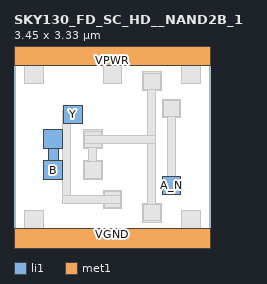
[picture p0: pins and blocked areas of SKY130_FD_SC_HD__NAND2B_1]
MACRO SKY130_FD_SC_HD__NAND2B_1
 CLASS CORE ;
 FOREIGN SKY130_FD_SC_HD__NAND2B_1 0 0 ;
 SIZE 3.45 BY 3.33 ;
 ORIGIN 0 0 ;
 SYMMETRY X Y R90 ;
 SITE unit ;
  PIN VPWR
   DIRECTION INOUT ;
   USE POWER ;
   SHAPE ABUTMENT ;
    PORT
     CLASS CORE ;
       LAYER li1 ;
        RECT 0.00000000 3.09000000 3.45000000 3.57000000 ;
       LAYER met1 ;
        RECT 0.00000000 3.09000000 3.45000000 3.57000000 ;
    END
  END VPWR

  PIN VGND
   DIRECTION INOUT ;
   USE POWER ;
   SHAPE ABUTMENT ;
    PORT
     CLASS CORE ;
       LAYER li1 ;
        RECT 0.00000000 -0.24000000 3.45000000 0.24000000 ;
       LAYER met1 ;
        RECT 0.00000000 -0.24000000 3.45000000 0.24000000 ;
    END
  END VGND

  PIN Y
   DIRECTION INOUT ;
   USE SIGNAL ;
   SHAPE ABUTMENT ;
    PORT
     CLASS CORE ;
       LAYER li1 ;
        RECT 0.87000000 2.07000000 1.20000000 2.40000000 ;
    END
  END Y

  PIN A_N
   DIRECTION INOUT ;
   USE SIGNAL ;
   SHAPE ABUTMENT ;
    PORT
     CLASS CORE ;
       LAYER li1 ;
        RECT 2.59500000 0.82500000 2.92500000 1.15500000 ;
    END
  END A_N

  PIN B
   DIRECTION INOUT ;
   USE SIGNAL ;
   SHAPE ABUTMENT ;
    PORT
     CLASS CORE ;
       LAYER li1 ;
        RECT 0.52500000 1.09500000 0.85500000 1.42500000 ;
        RECT 0.60500000 1.42500000 0.77500000 1.63500000 ;
        RECT 0.52500000 1.63500000 0.85500000 1.96500000 ;
    END
  END B

 OBS
    LAYER polycont ;
     RECT 2.67500000 0.90500000 2.84500000 1.07500000 ;
     RECT 0.60500000 1.17500000 0.77500000 1.34500000 ;
     RECT 1.29500000 1.17500000 1.46500000 1.34500000 ;
     RECT 0.60500000 1.71500000 0.77500000 1.88500000 ;
     RECT 1.29500000 1.71500000 1.46500000 1.88500000 ;
     RECT 2.67500000 2.25500000 2.84500000 2.42500000 ;

    LAYER pdiffc ;
     RECT 0.95000000 2.15000000 1.12000000 2.32000000 ;
     RECT 2.33000000 2.73000000 2.50000000 2.90000000 ;
     RECT 0.26000000 2.86000000 0.43000000 3.03000000 ;
     RECT 1.64000000 2.86000000 1.81000000 3.03000000 ;
     RECT 3.02000000 2.86000000 3.19000000 3.03000000 ;

    LAYER ndiffc ;
     RECT 0.26000000 0.30000000 0.43000000 0.47000000 ;
     RECT 3.02000000 0.30000000 3.19000000 0.47000000 ;
     RECT 2.33000000 0.43000000 2.50000000 0.60000000 ;
     RECT 1.64000000 0.66000000 1.81000000 0.83000000 ;

    LAYER li1 ;
     RECT 0.00000000 -0.24000000 3.45000000 0.24000000 ;
     RECT 0.18000000 0.24000000 0.51000000 0.55000000 ;
     RECT 2.94000000 0.24000000 3.27000000 0.55000000 ;
     RECT 2.25000000 0.35000000 2.58000000 0.68000000 ;
     RECT 1.56000000 0.58000000 1.89000000 0.91000000 ;
     RECT 2.59500000 0.82500000 2.92500000 1.15500000 ;
     RECT 1.21500000 1.09500000 1.54500000 1.42500000 ;
     RECT 0.52500000 1.09500000 0.85500000 1.42500000 ;
     RECT 0.60500000 1.42500000 0.77500000 1.63500000 ;
     RECT 0.52500000 1.63500000 0.85500000 1.96500000 ;
     RECT 1.21500000 1.63500000 1.54500000 1.96500000 ;
     RECT 0.87000000 2.07000000 1.20000000 2.40000000 ;
     RECT 2.59500000 2.17500000 2.92500000 2.50500000 ;
     RECT 2.25000000 2.65000000 2.58000000 2.98000000 ;
     RECT 0.18000000 2.78000000 0.51000000 3.09000000 ;
     RECT 1.56000000 2.78000000 1.89000000 3.09000000 ;
     RECT 2.94000000 2.78000000 3.27000000 3.09000000 ;
     RECT 0.00000000 3.09000000 3.45000000 3.57000000 ;

    LAYER viali ;
     RECT 3.02000000 -0.08500000 3.19000000 0.08500000 ;
     RECT 2.33000000 0.43000000 2.50000000 0.60000000 ;
     RECT 1.64000000 0.66000000 1.81000000 0.83000000 ;
     RECT 2.67500000 0.90500000 2.84500000 1.07500000 ;
     RECT 1.29500000 1.17500000 1.46500000 1.34500000 ;
     RECT 1.29500000 1.71500000 1.46500000 1.88500000 ;
     RECT 0.95000000 2.15000000 1.12000000 2.32000000 ;
     RECT 2.67500000 2.25500000 2.84500000 2.42500000 ;
     RECT 2.33000000 2.73000000 2.50000000 2.90000000 ;
     RECT 1.64000000 3.24500000 1.81000000 3.41500000 ;

    LAYER met1 ;
     RECT 0.00000000 -0.24000000 3.45000000 0.24000000 ;
     RECT 1.58000000 0.60000000 1.87000000 0.67500000 ;
     RECT 0.85000000 0.67500000 1.87000000 0.81500000 ;
     RECT 1.58000000 0.81500000 1.87000000 0.89000000 ;
     RECT 0.85000000 0.81500000 0.99000000 2.09000000 ;
     RECT 0.85000000 2.09000000 1.18000000 2.30500000 ;
     RECT 0.89000000 2.30500000 1.18000000 2.38000000 ;
     RECT 2.61500000 0.84500000 2.90500000 1.13500000 ;
     RECT 2.69000000 1.13500000 2.83000000 2.19500000 ;
     RECT 2.61500000 2.19500000 2.90500000 2.48500000 ;
     RECT 2.27000000 0.37000000 2.56000000 0.66000000 ;
     RECT 1.23500000 1.11500000 1.52500000 1.40500000 ;
     RECT 1.31000000 1.40500000 1.45000000 1.65500000 ;
     RECT 1.23500000 1.65500000 1.52500000 1.73000000 ;
     RECT 2.34500000 0.66000000 2.48500000 1.73000000 ;
     RECT 1.23500000 1.73000000 2.48500000 1.87000000 ;
     RECT 1.23500000 1.87000000 1.52500000 1.94500000 ;
     RECT 2.34500000 1.87000000 2.48500000 2.67000000 ;
     RECT 2.27000000 2.67000000 2.56000000 2.96000000 ;
     RECT 0.00000000 3.09000000 3.45000000 3.57000000 ;

    LAYER via ;


    LAYER met2 ;


    LAYER via2 ;


    LAYER met3 ;


 END
END SKY130_FD_SC_HD__NAND2B_1
